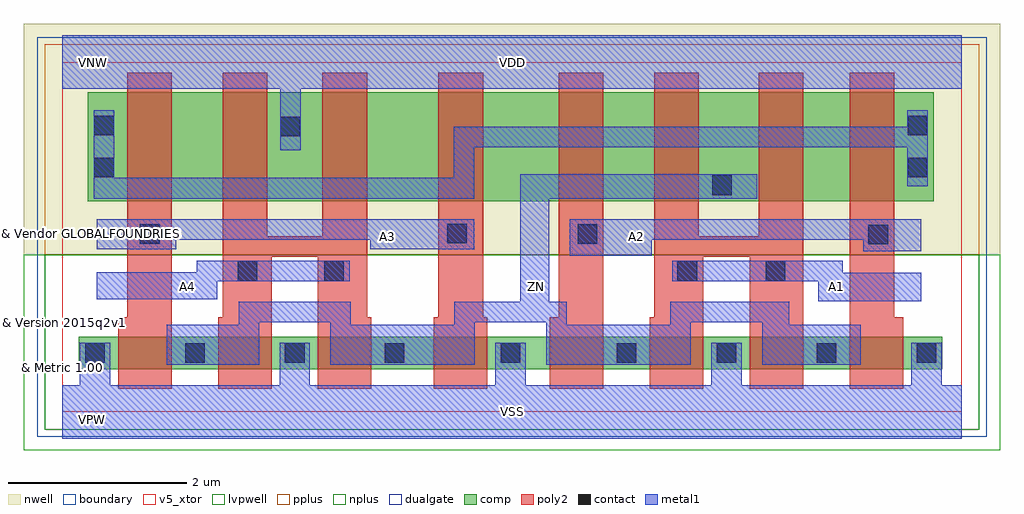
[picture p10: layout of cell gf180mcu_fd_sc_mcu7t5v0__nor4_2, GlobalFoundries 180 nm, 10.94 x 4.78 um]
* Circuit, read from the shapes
.subckt gf180mcu_fd_sc_mcu7t5v0__nor4_2 A1 A2 A3 A4 VDD VNW VSS ZN
XM1 ZN A3 VSS VSUBS nfet_05v0 w=0.36u l=0.6u m=2
XM2 VSS A4 ZN VSUBS nfet_05v0 w=0.36u l=0.6u m=2
XM3 ZN A2 VSS VSUBS nfet_05v0 w=0.36u l=0.6u m=2
XM4 VSS A1 ZN VSUBS nfet_05v0 w=0.36u l=0.6u m=2
XM5 n1 A3 n2 VNW pfet_05v0 w=1.22u l=0.5u
XM6 VDD A4 n1 VNW pfet_05v0 w=1.22u l=0.5u
XM7 n3 A4 VDD VNW pfet_05v0 w=1.22u l=0.5u
XM8 n4 A3 n3 VNW pfet_05v0 w=1.22u l=0.5u
XM9 n5 A2 n4 VNW pfet_05v0 w=1.22u l=0.5u
XM10 ZN A1 n5 VNW pfet_05v0 w=1.22u l=0.5u
XM11 n6 A1 ZN VNW pfet_05v0 w=1.22u l=0.5u
XM12 n2 A2 n6 VNW pfet_05v0 w=1.22u l=0.5u
.ends

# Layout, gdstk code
import gdstk
lib = gdstk.Library(unit=1e-6, precision=1e-09)
def R(c, l, rs):  # rectangles x0, y0, x1, y1
    for r in rs: c.add(gdstk.rectangle(r[:2], r[2:], *l))
def A(c, l, x, y, w, h, nx, ny, dx, dy):  # array of equal rectangles
    R(c, l, [(x+i*dx, y+j*dy, x+i*dx+w, y+j*dy+h) for i in range(nx) for j in range(ny)])
def P(c, l, *ps):  # polygons
    for p in ps: c.add(gdstk.Polygon(p, *l))
boundary = (0, 0)
nwell = (21, 0)
comp = (22, 0)
poly2 = (30, 0)
pplus = (31, 0)
nplus = (32, 0)
contact = (33, 0)
metal1 = (34, 0)
dualgate = (55, 0)
v5_xtor = (112, 1)
lvpwell = (204, 0)

gf180mcu_fd_sc_mcu7t5v0_ = lib.new_cell('gf180mcu_fd_sc_mcu7t5v0__nor4_2')
R(gf180mcu_fd_sc_mcu7t5v0_, boundary, [(0,0,10.08,3.92)])
R(gf180mcu_fd_sc_mcu7t5v0_, nwell, [(-0.43,1.76,10.51,4.35)])
R(gf180mcu_fd_sc_mcu7t5v0_, comp, [(0.185,0.48,9.865,0.84), (0.285,2.36,9.765,3.58)])
P(gf180mcu_fd_sc_mcu7t5v0_, poly2, [(0.625,0.26),(0.625,1.06),(0.725,1.06),(0.725,3.8),(1.225,3.8),(1.225,0.26)],
  [(1.745,0.26),(1.745,1.06),(1.795,1.06),(1.795,3.8),(2.295,3.8),(2.295,1.97),(2.915,1.97),(2.915,3.8),(3.415,3.8),(3.415,1.06),(3.465,1.06),(3.465,0.26),(2.865,0.26),(2.865,1.74),(2.345,1.74),(2.345,0.26)],
  [(4.165,0.26),(4.165,1.06),(4.215,1.06),(4.215,3.8),(4.715,3.8),(4.715,1.06),(4.765,1.06),(4.765,0.26)],
  [(5.465,0.26),(5.465,1.06),(5.565,1.06),(5.565,3.8),(6.065,3.8),(6.065,0.26)],
  [(6.585,0.26),(6.585,1.06),(6.635,1.06),(6.635,3.8),(7.135,3.8),(7.135,1.97),(7.805,1.97),(7.805,3.8),(8.305,3.8),(8.305,0.26),(7.705,0.26),(7.705,1.74),(7.185,1.74),(7.185,0.26)],
  [(8.825,0.26),(8.825,3.8),(9.325,3.8),(9.325,1.06),(9.425,1.06),(9.425,0.26)])
R(gf180mcu_fd_sc_mcu7t5v0_, pplus, [(-0.2,1.76,10.28,4.12)])
R(gf180mcu_fd_sc_mcu7t5v0_, nplus, [(-0.2,-0.2,10.28,1.76)])
A(gf180mcu_fd_sc_mcu7t5v0_, contact, 0.255, 0.55, 0.22, 0.22, 4, 1, 1.12, 0)
A(gf180mcu_fd_sc_mcu7t5v0_, contact, 6.215, 0.55, 0.22, 0.22, 4, 1, 1.12, 0)
R(gf180mcu_fd_sc_mcu7t5v0_, contact, [(4.915,0.55,5.135,0.77), (1.965,1.47,2.185,1.69), (2.935,1.47,3.155,1.69), (6.895,1.47,7.115,1.69), (7.885,1.47,8.105,1.69), (9.035,1.88,9.255,2.1), (0.87,1.885,1.09,2.105), (5.775,1.885,5.995,2.105), (4.315,1.89,4.535,2.11), (7.285,2.43,7.505,2.65), (0.355,2.63,0.575,2.85), (9.475,2.63,9.695,2.85), (2.445,3.09,2.665,3.31), (0.355,3.1,0.575,3.32), (9.475,3.1,9.695,3.32)])
P(gf180mcu_fd_sc_mcu7t5v0_, metal1, [(0.385,1.265),(0.385,1.565),(1.505,1.565),(1.505,1.695),(3.22,1.695),(3.22,1.465),(1.735,1.465),(1.735,1.265)],
  [(0.385,1.825),(0.385,2.16),(4.615,2.16),(4.615,1.825),(3.45,1.825),(3.45,1.93),(1.275,1.93),(1.275,1.825)],
  [(1.17,0.53),(1.17,0.975),(1.975,0.975),(1.975,1.235),(3.235,1.235),(3.235,0.975),(4.395,0.975),(4.395,1.235),(5.13,1.235),(5.13,2.665),(7.79,2.665),(7.79,2.39),(5.46,2.39),(5.46,1.235),(5.655,1.235),(5.655,0.975),(6.815,0.975),(6.815,1.235),(8.145,1.235),(8.145,0.975),(8.95,0.975),(8.95,0.53),(7.845,0.53),(7.845,1.005),(7.045,1.005),(7.045,0.53),(5.425,0.53),(5.425,1.005),(4.625,1.005),(4.625,0.53),(3.005,0.53),(3.005,1.005),(2.205,1.005),(2.205,0.53)],
  [(8.47,1.24),(8.47,1.465),(6.835,1.465),(6.835,1.695),(8.745,1.695),(8.745,1.56),(9.63,1.56),(9.63,1.24)],
  [(5.69,1.75),(5.69,2.16),(9.63,2.16),(9.63,1.8),(8.975,1.8),(8.975,1.93),(6.605,1.93),(6.605,1.75)],
  [(0.35,2.39),(0.35,3.38),(0.58,3.38),(0.58,2.625),(4.385,2.625),(4.385,3.195),(9.47,3.195),(9.47,3.38),(9.7,3.38),(9.7,2.53),(9.47,2.53),(9.47,2.965),(4.615,2.965),(4.615,2.39)],
  [(0,-0.3),(0,0.3),(0.195,0.3),(0.195,0.775),(0.535,0.775),(0.535,0.3),(2.435,0.3),(2.435,0.775),(2.775,0.775),(2.775,0.3),(4.855,0.3),(4.855,0.775),(5.195,0.775),(5.195,0.3),(7.275,0.3),(7.275,0.775),(7.615,0.775),(7.615,0.3),(9.515,0.3),(9.515,0.775),(9.855,0.775),(9.855,0.3),(10.08,0.3),(10.08,-0.3)],
  [(2.44,2.935),(2.44,3.62),(0,3.62),(0,4.22),(10.08,4.22),(10.08,3.62),(2.67,3.62),(2.67,2.935)])
R(gf180mcu_fd_sc_mcu7t5v0_, dualgate, [(-0.28,-0.28,10.36,4.2)])
R(gf180mcu_fd_sc_mcu7t5v0_, v5_xtor, [(0,0,10.08,3.92)])
R(gf180mcu_fd_sc_mcu7t5v0_, lvpwell, [(-0.43,-0.43,10.51,1.76)])
gf180mcu_fd_sc_mcu7t5v0_.add(gdstk.Label('A3', (3.64,1.96), layer=34, texttype=10))
gf180mcu_fd_sc_mcu7t5v0_.add(gdstk.Label('A4', (1.4,1.4), layer=34, texttype=10))
gf180mcu_fd_sc_mcu7t5v0_.add(gdstk.Label('VDD', (5.04,3.92), layer=34, texttype=10))
gf180mcu_fd_sc_mcu7t5v0_.add(gdstk.Label('VSS', (5.04,0), layer=34, texttype=10))
gf180mcu_fd_sc_mcu7t5v0_.add(gdstk.Label('ZN', (5.32,1.4), layer=34, texttype=10))
gf180mcu_fd_sc_mcu7t5v0_.add(gdstk.Label('A1', (8.68,1.4), layer=34, texttype=10))
gf180mcu_fd_sc_mcu7t5v0_.add(gdstk.Label('A2', (6.44,1.96), layer=34, texttype=10))
gf180mcu_fd_sc_mcu7t5v0_.add(gdstk.Label('& Vendor GLOBALFOUNDRIES', (0,2), layer=63, texttype=63))
gf180mcu_fd_sc_mcu7t5v0_.add(gdstk.Label('& Product GF018hv5v_mcu_sc7', (0,1.5), layer=63, texttype=63))
gf180mcu_fd_sc_mcu7t5v0_.add(gdstk.Label('& Version 2015q2v1', (0,1), layer=63, texttype=63))
gf180mcu_fd_sc_mcu7t5v0_.add(gdstk.Label('& Metric 1.00', (0,0.5), layer=63, texttype=63))
gf180mcu_fd_sc_mcu7t5v0_.add(gdstk.Label('VNW', (0.345,3.92), layer=21, texttype=10))
gf180mcu_fd_sc_mcu7t5v0_.add(gdstk.Label('VPW', (0.34,-0.085), layer=204, texttype=10))

lib.write_gds('gf180mcu_fd_sc_mcu7t5v0__nor4_2.gds')
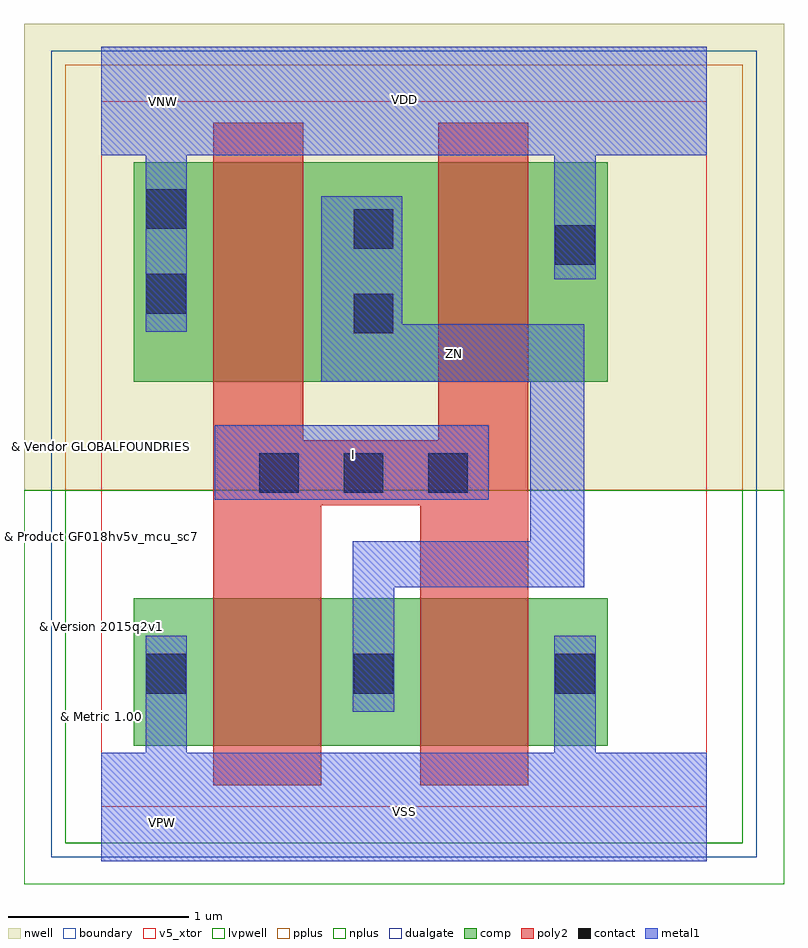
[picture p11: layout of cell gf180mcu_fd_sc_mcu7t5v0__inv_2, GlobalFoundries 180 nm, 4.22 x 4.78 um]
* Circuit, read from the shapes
.subckt gf180mcu_fd_sc_mcu7t5v0__inv_2 I VDD VNW VSS ZN
XM1 ZN I VSS VSUBS nfet_05v0 w=0.82u l=0.6u m=2
XM2 ZN I VDD VNW pfet_05v0 w=1.22u l=0.5u m=2
.ends

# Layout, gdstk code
import gdstk
lib = gdstk.Library(unit=1e-6, precision=1e-09)
def R(c, l, rs):  # rectangles x0, y0, x1, y1
    for r in rs: c.add(gdstk.rectangle(r[:2], r[2:], *l))
def A(c, l, x, y, w, h, nx, ny, dx, dy):  # array of equal rectangles
    R(c, l, [(x+i*dx, y+j*dy, x+i*dx+w, y+j*dy+h) for i in range(nx) for j in range(ny)])
def P(c, l, *ps):  # polygons
    for p in ps: c.add(gdstk.Polygon(p, *l))
boundary = (0, 0)
nwell = (21, 0)
comp = (22, 0)
poly2 = (30, 0)
pplus = (31, 0)
nplus = (32, 0)
contact = (33, 0)
metal1 = (34, 0)
dualgate = (55, 0)
v5_xtor = (112, 1)
lvpwell = (204, 0)

gf180mcu_fd_sc_mcu7t5v0_ = lib.new_cell('gf180mcu_fd_sc_mcu7t5v0__inv_2')
R(gf180mcu_fd_sc_mcu7t5v0_, boundary, [(0,0,3.36,3.92)])
R(gf180mcu_fd_sc_mcu7t5v0_, nwell, [(-0.43,1.76,3.79,4.35)])
R(gf180mcu_fd_sc_mcu7t5v0_, comp, [(0.18,0.34,2.81,1.16), (0.18,2.36,2.81,3.58)])
P(gf180mcu_fd_sc_mcu7t5v0_, poly2, [(0.62,0.12),(0.62,3.8),(1.12,3.8),(1.12,2.035),(1.87,2.035),(1.87,3.8),(2.37,3.8),(2.37,0.12),(1.77,0.12),(1.77,1.675),(1.22,1.675),(1.22,0.12)])
R(gf180mcu_fd_sc_mcu7t5v0_, pplus, [(-0.2,1.76,3.56,4.12)])
R(gf180mcu_fd_sc_mcu7t5v0_, nplus, [(-0.2,-0.2,3.56,1.76)])
A(gf180mcu_fd_sc_mcu7t5v0_, contact, 0.875, 1.745, 0.22, 0.22, 3, 1, 0.47, 0)
R(gf180mcu_fd_sc_mcu7t5v0_, contact, [(0.25,0.63,0.47,0.85), (1.4,0.63,1.62,0.85), (2.52,0.63,2.74,0.85), (1.4,2.63,1.62,2.85), (0.25,2.74,0.47,2.96), (2.52,3.01,2.74,3.23), (1.4,3.1,1.62,3.32), (0.25,3.21,0.47,3.43)])
R(gf180mcu_fd_sc_mcu7t5v0_, metal1, [(0.63,1.705,2.15,2.12)])
P(gf180mcu_fd_sc_mcu7t5v0_, metal1, [(1.395,0.53),(1.395,1.475),(2.38,1.475),(2.38,2.36),(1.22,2.36),(1.22,3.39),(1.67,3.39),(1.67,2.68),(2.68,2.68),(2.68,1.22),(1.625,1.22),(1.625,0.53)],
  [(0,-0.3),(0,0.3),(0.245,0.3),(0.245,0.95),(0.475,0.95),(0.475,0.3),(2.515,0.3),(2.515,0.95),(2.745,0.95),(2.745,0.3),(3.36,0.3),(3.36,-0.3)],
  [(0.245,2.64),(0.245,3.62),(0,3.62),(0,4.22),(3.36,4.22),(3.36,3.62),(2.745,3.62),(2.745,2.93),(2.515,2.93),(2.515,3.62),(0.475,3.62),(0.475,2.64)])
R(gf180mcu_fd_sc_mcu7t5v0_, dualgate, [(-0.28,-0.28,3.64,4.2)])
R(gf180mcu_fd_sc_mcu7t5v0_, v5_xtor, [(0,0,3.36,3.92)])
R(gf180mcu_fd_sc_mcu7t5v0_, lvpwell, [(-0.43,-0.43,3.79,1.76)])
gf180mcu_fd_sc_mcu7t5v0_.add(gdstk.Label('VSS', (1.68,-0.025), layer=34, texttype=10))
gf180mcu_fd_sc_mcu7t5v0_.add(gdstk.Label('ZN', (1.96,2.52), layer=34, texttype=10))
gf180mcu_fd_sc_mcu7t5v0_.add(gdstk.Label('I', (1.4,1.96), layer=34, texttype=10))
gf180mcu_fd_sc_mcu7t5v0_.add(gdstk.Label('VDD', (1.68,3.93), layer=34, texttype=10))
gf180mcu_fd_sc_mcu7t5v0_.add(gdstk.Label('& Vendor GLOBALFOUNDRIES', (0,2), layer=63, texttype=63))
gf180mcu_fd_sc_mcu7t5v0_.add(gdstk.Label('& Product GF018hv5v_mcu_sc7', (0,1.5), layer=63, texttype=63))
gf180mcu_fd_sc_mcu7t5v0_.add(gdstk.Label('& Version 2015q2v1', (0,1), layer=63, texttype=63))
gf180mcu_fd_sc_mcu7t5v0_.add(gdstk.Label('& Metric 1.00', (0,0.5), layer=63, texttype=63))
gf180mcu_fd_sc_mcu7t5v0_.add(gdstk.Label('VNW', (0.345,3.92), layer=21, texttype=10))
gf180mcu_fd_sc_mcu7t5v0_.add(gdstk.Label('VPW', (0.34,-0.085), layer=204, texttype=10))

lib.write_gds('gf180mcu_fd_sc_mcu7t5v0__inv_2.gds')
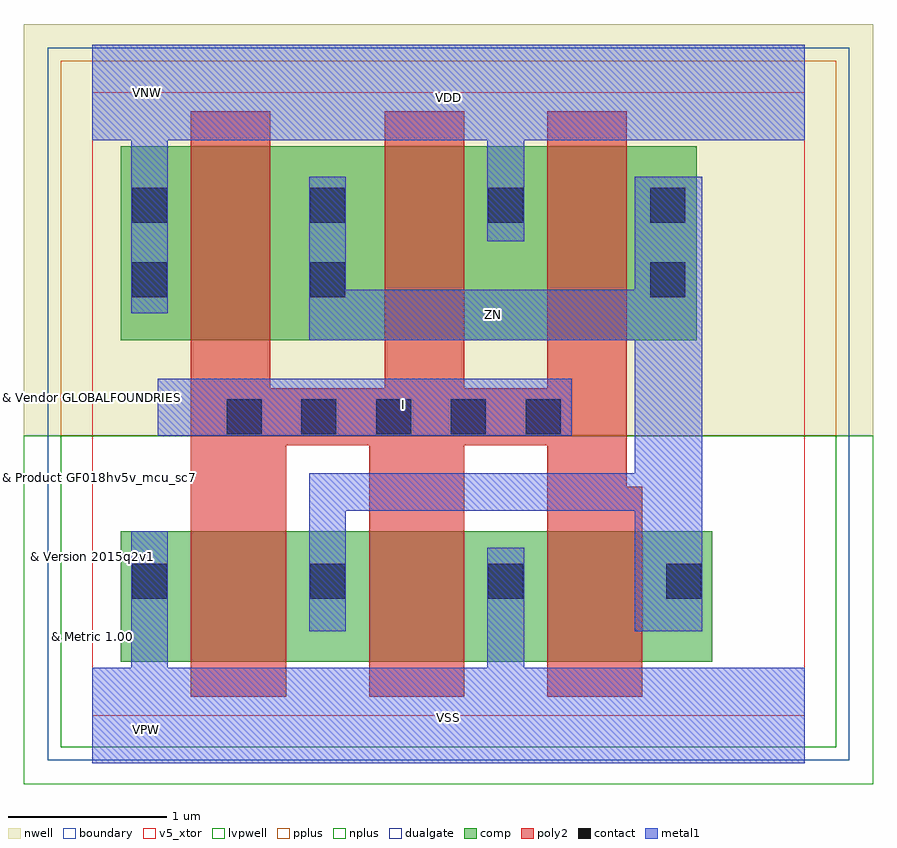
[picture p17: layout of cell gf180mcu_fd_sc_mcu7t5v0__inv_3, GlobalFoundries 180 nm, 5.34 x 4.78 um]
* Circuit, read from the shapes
.subckt gf180mcu_fd_sc_mcu7t5v0__inv_3 I VDD VNW VSS ZN
XM1 ZN I VSS VSUBS nfet_05v0 w=0.82u l=0.6u m=3
XM2 ZN I VDD VNW pfet_05v0 w=1.22u l=0.5u m=3
.ends

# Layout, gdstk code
import gdstk
lib = gdstk.Library(unit=1e-6, precision=1e-09)
def R(c, l, rs):  # rectangles x0, y0, x1, y1
    for r in rs: c.add(gdstk.rectangle(r[:2], r[2:], *l))
def A(c, l, x, y, w, h, nx, ny, dx, dy):  # array of equal rectangles
    R(c, l, [(x+i*dx, y+j*dy, x+i*dx+w, y+j*dy+h) for i in range(nx) for j in range(ny)])
def P(c, l, *ps):  # polygons
    for p in ps: c.add(gdstk.Polygon(p, *l))
boundary = (0, 0)
nwell = (21, 0)
comp = (22, 0)
poly2 = (30, 0)
pplus = (31, 0)
nplus = (32, 0)
contact = (33, 0)
metal1 = (34, 0)
dualgate = (55, 0)
v5_xtor = (112, 1)
lvpwell = (204, 0)

gf180mcu_fd_sc_mcu7t5v0_ = lib.new_cell('gf180mcu_fd_sc_mcu7t5v0__inv_3')
R(gf180mcu_fd_sc_mcu7t5v0_, boundary, [(0,0,4.48,3.92)])
R(gf180mcu_fd_sc_mcu7t5v0_, nwell, [(-0.43,1.76,4.91,4.35)])
R(gf180mcu_fd_sc_mcu7t5v0_, comp, [(0.18,0.34,3.9,1.16), (0.18,2.36,3.8,3.58)])
P(gf180mcu_fd_sc_mcu7t5v0_, poly2, [(0.62,0.12),(0.62,3.8),(1.12,3.8),(1.12,2.06),(1.84,2.06),(1.84,3.8),(2.34,3.8),(2.34,2.06),(2.86,2.06),(2.86,3.8),(3.36,3.8),(3.36,1.44),(3.46,1.44),(3.46,0.12),(2.86,0.12),(2.86,1.7),(2.34,1.7),(2.34,0.12),(1.74,0.12),(1.74,1.7),(1.22,1.7),(1.22,0.12)])
R(gf180mcu_fd_sc_mcu7t5v0_, pplus, [(-0.2,1.76,4.68,4.12)])
R(gf180mcu_fd_sc_mcu7t5v0_, nplus, [(-0.2,-0.2,4.68,1.76)])
A(gf180mcu_fd_sc_mcu7t5v0_, contact, 0.25, 0.735, 0.22, 0.22, 4, 1, 1.12, 0)
A(gf180mcu_fd_sc_mcu7t5v0_, contact, 0.845, 1.77, 0.22, 0.22, 5, 1, 0.47, 0)
A(gf180mcu_fd_sc_mcu7t5v0_, contact, 0.25, 3.1, 0.22, 0.22, 3, 1, 1.12, 0)
R(gf180mcu_fd_sc_mcu7t5v0_, contact, [(0.25,2.63,0.47,2.85), (1.37,2.63,1.59,2.85), (3.51,2.63,3.73,2.85), (3.51,3.1,3.73,3.32)])
R(gf180mcu_fd_sc_mcu7t5v0_, metal1, [(0.41,1.76,3.015,2.12)])
P(gf180mcu_fd_sc_mcu7t5v0_, metal1, [(1.365,0.53),(1.365,1.525),(3.41,1.525),(3.41,2.36),(1.365,2.36),(1.365,3.39),(1.595,3.39),(1.595,2.68),(3.41,2.68),(3.41,3.39),(3.835,3.39),(3.835,0.53),(3.41,0.53),(3.41,1.29),(1.595,1.29),(1.595,0.53)],
  [(0,-0.3),(0,0.3),(0.245,0.3),(0.245,1.16),(0.475,1.16),(0.475,0.3),(2.485,0.3),(2.485,1.055),(2.715,1.055),(2.715,0.3),(4.48,0.3),(4.48,-0.3)],
  [(0.245,2.53),(0.245,3.62),(0,3.62),(0,4.22),(4.48,4.22),(4.48,3.62),(2.715,3.62),(2.715,2.985),(2.485,2.985),(2.485,3.62),(0.475,3.62),(0.475,2.53)])
R(gf180mcu_fd_sc_mcu7t5v0_, dualgate, [(-0.28,-0.28,4.76,4.2)])
R(gf180mcu_fd_sc_mcu7t5v0_, v5_xtor, [(0,0,4.48,3.92)])
R(gf180mcu_fd_sc_mcu7t5v0_, lvpwell, [(-0.43,-0.43,4.91,1.76)])
gf180mcu_fd_sc_mcu7t5v0_.add(gdstk.Label('VSS', (2.24,-0.01), layer=34, texttype=10))
gf180mcu_fd_sc_mcu7t5v0_.add(gdstk.Label('ZN', (2.52,2.52), layer=34, texttype=10))
gf180mcu_fd_sc_mcu7t5v0_.add(gdstk.Label('I', (1.96,1.96), layer=34, texttype=10))
gf180mcu_fd_sc_mcu7t5v0_.add(gdstk.Label('VDD', (2.24,3.885), layer=34, texttype=10))
gf180mcu_fd_sc_mcu7t5v0_.add(gdstk.Label('& Vendor GLOBALFOUNDRIES', (0,2), layer=63, texttype=63))
gf180mcu_fd_sc_mcu7t5v0_.add(gdstk.Label('& Product GF018hv5v_mcu_sc7', (0,1.5), layer=63, texttype=63))
gf180mcu_fd_sc_mcu7t5v0_.add(gdstk.Label('& Version 2015q2v1', (0,1), layer=63, texttype=63))
gf180mcu_fd_sc_mcu7t5v0_.add(gdstk.Label('& Metric 1.00', (0,0.5), layer=63, texttype=63))
gf180mcu_fd_sc_mcu7t5v0_.add(gdstk.Label('VNW', (0.345,3.92), layer=21, texttype=10))
gf180mcu_fd_sc_mcu7t5v0_.add(gdstk.Label('VPW', (0.34,-0.085), layer=204, texttype=10))

lib.write_gds('gf180mcu_fd_sc_mcu7t5v0__inv_3.gds')
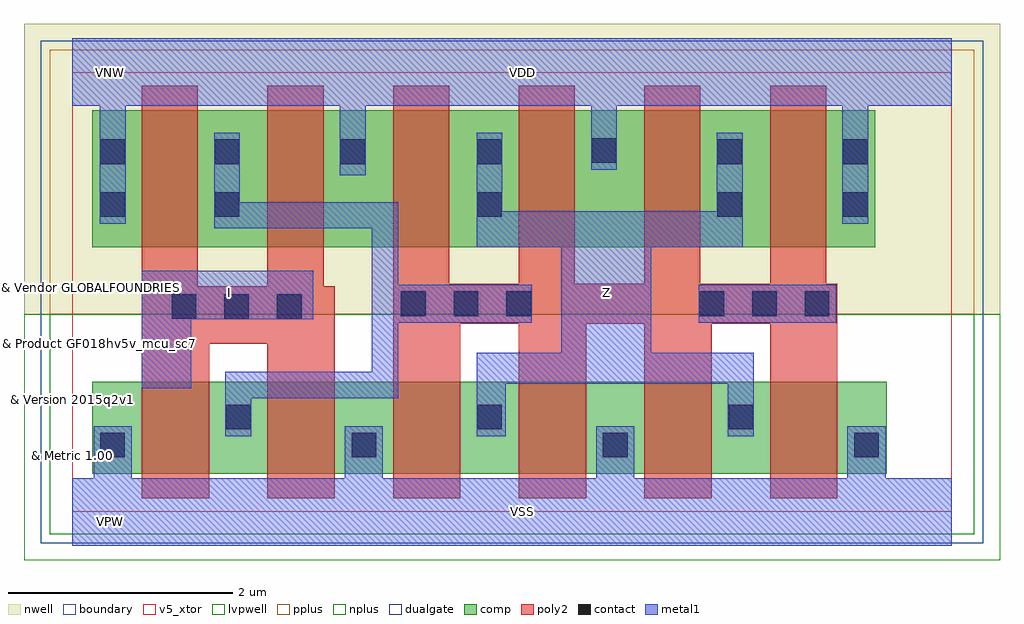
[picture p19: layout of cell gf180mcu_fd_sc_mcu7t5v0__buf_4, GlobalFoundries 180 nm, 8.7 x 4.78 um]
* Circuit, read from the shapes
.subckt gf180mcu_fd_sc_mcu7t5v0__buf_4 I VDD VNW VSS Z
XM1 n1 I VSS VSUBS nfet_05v0 w=0.82u l=0.6u m=2
XM2 Z n1 VSS VSUBS nfet_05v0 w=0.82u l=0.6u m=4
XM3 n1 I VDD VNW pfet_05v0 w=1.22u l=0.5u m=2
XM4 Z n1 VDD VNW pfet_05v0 w=1.22u l=0.5u m=4
.ends

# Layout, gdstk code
import gdstk
lib = gdstk.Library(unit=1e-6, precision=1e-09)
def R(c, l, rs):  # rectangles x0, y0, x1, y1
    for r in rs: c.add(gdstk.rectangle(r[:2], r[2:], *l))
def A(c, l, x, y, w, h, nx, ny, dx, dy):  # array of equal rectangles
    R(c, l, [(x+i*dx, y+j*dy, x+i*dx+w, y+j*dy+h) for i in range(nx) for j in range(ny)])
def P(c, l, *ps):  # polygons
    for p in ps: c.add(gdstk.Polygon(p, *l))
boundary = (0, 0)
nwell = (21, 0)
comp = (22, 0)
poly2 = (30, 0)
pplus = (31, 0)
nplus = (32, 0)
contact = (33, 0)
metal1 = (34, 0)
dualgate = (55, 0)
v5_xtor = (112, 1)
lvpwell = (204, 0)

gf180mcu_fd_sc_mcu7t5v0_ = lib.new_cell('gf180mcu_fd_sc_mcu7t5v0__buf_4')
R(gf180mcu_fd_sc_mcu7t5v0_, boundary, [(0,0,7.84,3.92)])
R(gf180mcu_fd_sc_mcu7t5v0_, nwell, [(-0.43,1.76,8.27,4.35)])
R(gf180mcu_fd_sc_mcu7t5v0_, comp, [(0.18,0.34,7.26,1.16), (0.18,2.36,7.16,3.58)])
P(gf180mcu_fd_sc_mcu7t5v0_, poly2, [(0.62,0.12),(0.62,3.8),(1.12,3.8),(1.12,2.01),(1.74,2.01),(1.74,3.8),(2.24,3.8),(2.24,2.01),(2.34,2.01),(2.34,0.12),(1.74,0.12),(1.74,1.5),(1.22,1.5),(1.22,0.12)],
  [(2.86,0.12),(2.86,3.8),(3.36,3.8),(3.36,2.035),(3.98,2.035),(3.98,3.8),(4.48,3.8),(4.48,2.035),(5.1,2.035),(5.1,3.8),(5.6,3.8),(5.6,2.035),(6.22,2.035),(6.22,3.8),(6.72,3.8),(6.72,2.035),(6.82,2.035),(6.82,0.12),(6.22,0.12),(6.22,1.675),(5.7,1.675),(5.7,0.12),(5.1,0.12),(5.1,1.675),(4.58,1.675),(4.58,0.12),(3.98,0.12),(3.98,1.675),(3.46,1.675),(3.46,0.12)])
R(gf180mcu_fd_sc_mcu7t5v0_, pplus, [(-0.2,1.76,8.04,4.12)])
R(gf180mcu_fd_sc_mcu7t5v0_, nplus, [(-0.2,-0.2,8.04,1.76)])
A(gf180mcu_fd_sc_mcu7t5v0_, contact, 0.25, 0.485, 0.22, 0.22, 4, 1, 2.24, 0)
A(gf180mcu_fd_sc_mcu7t5v0_, contact, 1.37, 0.735, 0.22, 0.22, 3, 1, 2.24, 0)
A(gf180mcu_fd_sc_mcu7t5v0_, contact, 0.885, 1.72, 0.22, 0.22, 3, 1, 0.47, 0)
A(gf180mcu_fd_sc_mcu7t5v0_, contact, 2.93, 1.745, 0.22, 0.22, 3, 1, 0.47, 0)
A(gf180mcu_fd_sc_mcu7t5v0_, contact, 5.59, 1.745, 0.22, 0.22, 3, 1, 0.47, 0)
R(gf180mcu_fd_sc_mcu7t5v0_, contact, [(0.25,2.63,0.47,2.85), (1.27,2.63,1.49,2.85), (3.61,2.63,3.83,2.85), (5.75,2.63,5.97,2.85), (6.87,2.63,7.09,2.85), (0.25,3.1,0.47,3.32), (1.27,3.1,1.49,3.32), (2.39,3.1,2.61,3.32), (3.61,3.1,3.83,3.32), (5.75,3.1,5.97,3.32), (6.87,3.1,7.09,3.32), (4.63,3.11,4.85,3.33)])
R(gf180mcu_fd_sc_mcu7t5v0_, metal1, [(5.585,1.685,6.81,2.025)])
P(gf180mcu_fd_sc_mcu7t5v0_, metal1, [(0.62,1.1),(0.62,2.15),(2.15,2.15),(2.15,1.715),(1.06,1.715),(1.06,1.1)],
  [(1.365,0.675),(1.365,1.25),(2.67,1.25),(2.67,2.53),(1.265,2.53),(1.265,3.38),(1.495,3.38),(1.495,2.76),(2.905,2.76),(2.905,2.025),(4.095,2.025),(4.095,1.685),(2.905,1.685),(2.905,1.015),(1.595,1.015),(1.595,0.675)],
  [(3.605,0.675),(3.605,1.42),(4.36,1.42),(4.36,2.36),(3.605,2.36),(3.605,3.38),(3.835,3.38),(3.835,2.68),(5.745,2.68),(5.745,3.38),(5.975,3.38),(5.975,2.36),(5.16,2.36),(5.16,1.42),(6.075,1.42),(6.075,0.675),(5.845,0.675),(5.845,1.14),(3.865,1.14),(3.865,0.675)],
  [(0,-0.3),(0,0.3),(0.19,0.3),(0.19,0.765),(0.53,0.765),(0.53,0.3),(2.43,0.3),(2.43,0.765),(2.77,0.765),(2.77,0.3),(4.67,0.3),(4.67,0.765),(5.01,0.765),(5.01,0.3),(6.91,0.3),(6.91,0.765),(7.25,0.765),(7.25,0.3),(7.84,0.3),(7.84,-0.3)],
  [(0.245,2.57),(0.245,3.62),(0,3.62),(0,4.22),(7.84,4.22),(7.84,3.62),(7.095,3.62),(7.095,2.57),(6.865,2.57),(6.865,3.62),(4.855,3.62),(4.855,3.05),(4.625,3.05),(4.625,3.62),(2.615,3.62),(2.615,3),(2.385,3),(2.385,3.62),(0.475,3.62),(0.475,2.57)])
R(gf180mcu_fd_sc_mcu7t5v0_, dualgate, [(-0.28,-0.28,8.12,4.2)])
R(gf180mcu_fd_sc_mcu7t5v0_, v5_xtor, [(0,0,7.84,3.92)])
R(gf180mcu_fd_sc_mcu7t5v0_, lvpwell, [(-0.43,-0.43,8.27,1.76)])
gf180mcu_fd_sc_mcu7t5v0_.add(gdstk.Label('Z', (4.76,1.96), layer=34, texttype=10))
gf180mcu_fd_sc_mcu7t5v0_.add(gdstk.Label('I', (1.4,1.96), layer=34, texttype=10))
gf180mcu_fd_sc_mcu7t5v0_.add(gdstk.Label('VDD', (4.01,3.92), layer=34, texttype=10))
gf180mcu_fd_sc_mcu7t5v0_.add(gdstk.Label('VSS', (4.01,0), layer=34, texttype=10))
gf180mcu_fd_sc_mcu7t5v0_.add(gdstk.Label('& Vendor GLOBALFOUNDRIES', (0,2), layer=63, texttype=63))
gf180mcu_fd_sc_mcu7t5v0_.add(gdstk.Label('& Product GF018hv5v_mcu_sc7', (0,1.5), layer=63, texttype=63))
gf180mcu_fd_sc_mcu7t5v0_.add(gdstk.Label('& Version 2015q2v1', (0,1), layer=63, texttype=63))
gf180mcu_fd_sc_mcu7t5v0_.add(gdstk.Label('& Metric 1.00', (0,0.5), layer=63, texttype=63))
gf180mcu_fd_sc_mcu7t5v0_.add(gdstk.Label('VNW', (0.345,3.92), layer=21, texttype=10))
gf180mcu_fd_sc_mcu7t5v0_.add(gdstk.Label('VPW', (0.34,-0.085), layer=204, texttype=10))

lib.write_gds('gf180mcu_fd_sc_mcu7t5v0__buf_4.gds')
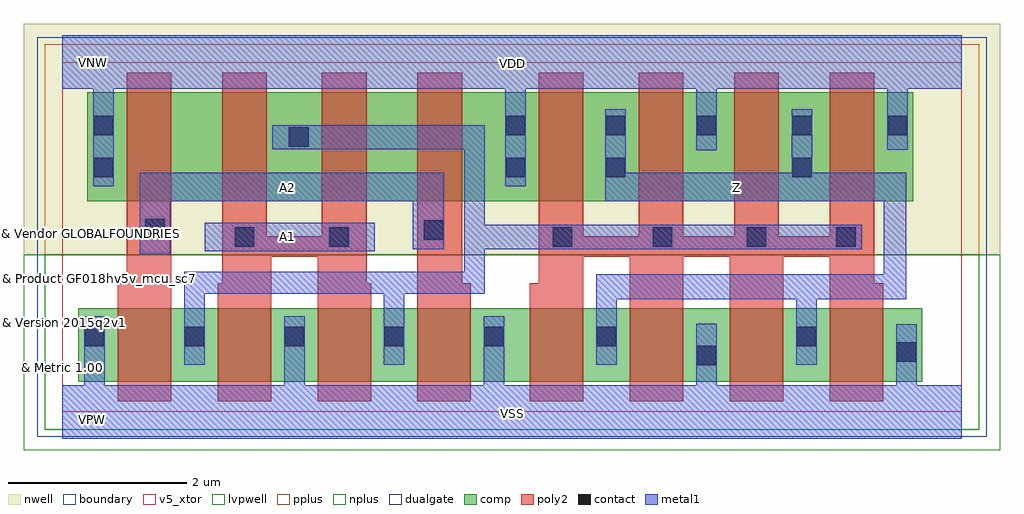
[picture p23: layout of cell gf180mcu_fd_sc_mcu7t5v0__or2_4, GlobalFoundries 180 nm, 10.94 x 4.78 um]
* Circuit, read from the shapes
.subckt gf180mcu_fd_sc_mcu7t5v0__or2_4 A1 A2 VDD VNW VSS Z
XM1 n1 A2 VSS VSUBS nfet_05v0 w=0.82u l=0.6u m=2
XM2 VSS A1 n1 VSUBS nfet_05v0 w=0.82u l=0.6u m=2
XM3 Z n1 VSS VSUBS nfet_05v0 w=0.82u l=0.6u m=4
XM4 n2 A2 VDD VNW pfet_05v0 w=1.22u l=0.5u
XM5 n1 A1 n2 VNW pfet_05v0 w=1.22u l=0.5u
XM6 n3 A1 n1 VNW pfet_05v0 w=1.22u l=0.5u
XM7 VDD A2 n3 VNW pfet_05v0 w=1.22u l=0.5u
XM8 Z n1 VDD VNW pfet_05v0 w=1.22u l=0.5u m=4
.ends

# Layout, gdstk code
import gdstk
lib = gdstk.Library(unit=1e-6, precision=1e-09)
def R(c, l, rs):  # rectangles x0, y0, x1, y1
    for r in rs: c.add(gdstk.rectangle(r[:2], r[2:], *l))
def A(c, l, x, y, w, h, nx, ny, dx, dy):  # array of equal rectangles
    R(c, l, [(x+i*dx, y+j*dy, x+i*dx+w, y+j*dy+h) for i in range(nx) for j in range(ny)])
def P(c, l, *ps):  # polygons
    for p in ps: c.add(gdstk.Polygon(p, *l))
boundary = (0, 0)
nwell = (21, 0)
comp = (22, 0)
poly2 = (30, 0)
pplus = (31, 0)
nplus = (32, 0)
contact = (33, 0)
metal1 = (34, 0)
dualgate = (55, 0)
v5_xtor = (112, 1)
lvpwell = (204, 0)

gf180mcu_fd_sc_mcu7t5v0_ = lib.new_cell('gf180mcu_fd_sc_mcu7t5v0__or2_4')
R(gf180mcu_fd_sc_mcu7t5v0_, boundary, [(0,0,10.08,3.92)])
R(gf180mcu_fd_sc_mcu7t5v0_, nwell, [(-0.43,1.76,10.51,4.35)])
R(gf180mcu_fd_sc_mcu7t5v0_, comp, [(0.18,0.34,9.64,1.16), (0.28,2.36,9.54,3.58)])
P(gf180mcu_fd_sc_mcu7t5v0_, poly2, [(0.62,0.12),(0.62,1.44),(0.72,1.44),(0.72,3.8),(1.22,3.8),(1.22,0.12)],
  [(1.74,0.12),(1.74,1.44),(1.79,1.44),(1.79,3.8),(2.29,3.8),(2.29,1.97),(2.91,1.97),(2.91,3.8),(3.41,3.8),(3.41,1.44),(3.46,1.44),(3.46,0.12),(2.86,0.12),(2.86,1.74),(2.34,1.74),(2.34,0.12)],
  [(3.98,0.12),(3.98,3.8),(4.48,3.8),(4.48,1.44),(4.58,1.44),(4.58,0.12)],
  [(5.24,0.12),(5.24,1.44),(5.34,1.44),(5.34,3.8),(5.84,3.8),(5.84,1.97),(6.46,1.97),(6.46,3.8),(6.96,3.8),(6.96,1.97),(7.53,1.97),(7.53,3.8),(8.03,3.8),(8.03,1.97),(8.6,1.97),(8.6,3.8),(9.1,3.8),(9.1,1.44),(9.2,1.44),(9.2,0.12),(8.6,0.12),(8.6,1.74),(8.08,1.74),(8.08,0.12),(7.48,0.12),(7.48,1.74),(6.96,1.74),(6.96,0.12),(6.36,0.12),(6.36,1.74),(5.84,1.74),(5.84,0.12)])
R(gf180mcu_fd_sc_mcu7t5v0_, pplus, [(-0.2,1.76,10.28,4.12)])
R(gf180mcu_fd_sc_mcu7t5v0_, nplus, [(-0.2,-0.2,10.28,1.76)])
A(gf180mcu_fd_sc_mcu7t5v0_, contact, 0.25, 0.735, 0.22, 0.22, 5, 1, 1.12, 0)
A(gf180mcu_fd_sc_mcu7t5v0_, contact, 7.11, 3.1, 0.22, 0.22, 3, 1, 1.07, 0)
R(gf180mcu_fd_sc_mcu7t5v0_, contact, [(7.11,0.52,7.33,0.74), (9.35,0.56,9.57,0.78), (5.99,0.735,6.21,0.955), (8.23,0.735,8.45,0.955), (1.93,1.85,2.15,2.07), (2.99,1.85,3.21,2.07), (5.495,1.85,5.715,2.07), (6.615,1.85,6.835,2.07), (7.67,1.85,7.89,2.07), (8.675,1.85,8.895,2.07), (4.05,1.93,4.27,2.15), (0.93,1.945,1.15,2.165), (0.35,2.63,0.57,2.85), (4.97,2.63,5.19,2.85), (6.09,2.63,6.31,2.85), (8.18,2.63,8.4,2.85), (2.54,2.97,2.76,3.19), (0.35,3.1,0.57,3.32), (4.97,3.1,5.19,3.32), (6.09,3.1,6.31,3.32)])
R(gf180mcu_fd_sc_mcu7t5v0_, metal1, [(1.595,1.8,3.5,2.12)])
P(gf180mcu_fd_sc_mcu7t5v0_, metal1, [(0.87,1.765),(0.87,2.68),(4.275,2.68),(4.275,1.825),(3.93,1.825),(3.93,2.36),(1.21,2.36),(1.21,1.765)],
  [(1.365,0.53),(1.365,1.57),(4.505,1.57),(4.505,2.945),(2.35,2.945),(2.35,3.215),(4.735,3.215),(4.735,2.095),(8.96,2.095),(8.96,1.825),(4.735,1.825),(4.735,1.325),(3.835,1.325),(3.835,0.53),(3.605,0.53),(3.605,1.325),(1.595,1.325),(1.595,0.53)],
  [(5.985,0.53),(5.985,1.54),(9.205,1.54),(9.205,2.36),(6.085,2.36),(6.085,3.39),(6.315,3.39),(6.315,2.68),(8.175,2.68),(8.175,3.39),(8.405,3.39),(8.405,2.68),(9.46,2.68),(9.46,1.265),(8.455,1.265),(8.455,0.53),(8.225,0.53),(8.225,1.26),(6.215,1.26),(6.215,0.53)],
  [(0,-0.3),(0,0.3),(0.245,0.3),(0.245,1.07),(0.475,1.07),(0.475,0.3),(2.485,0.3),(2.485,1.07),(2.715,1.07),(2.715,0.3),(4.725,0.3),(4.725,1.07),(4.955,1.07),(4.955,0.3),(7.105,0.3),(7.105,0.985),(7.335,0.985),(7.335,0.3),(9.345,0.3),(9.345,0.98),(9.575,0.98),(9.575,0.3),(10.08,0.3),(10.08,-0.3)],
  [(0.345,2.53),(0.345,3.62),(0,3.62),(0,4.22),(10.08,4.22),(10.08,3.62),(9.475,3.62),(9.475,2.94),(9.245,2.94),(9.245,3.62),(7.335,3.62),(7.335,2.935),(7.105,2.935),(7.105,3.62),(5.195,3.62),(5.195,2.53),(4.965,2.53),(4.965,3.62),(0.575,3.62),(0.575,2.53)])
R(gf180mcu_fd_sc_mcu7t5v0_, dualgate, [(-0.28,-0.28,10.36,4.2)])
R(gf180mcu_fd_sc_mcu7t5v0_, v5_xtor, [(0,0,10.08,3.92)])
R(gf180mcu_fd_sc_mcu7t5v0_, lvpwell, [(-0.43,-0.43,10.51,1.76)])
gf180mcu_fd_sc_mcu7t5v0_.add(gdstk.Label('VDD', (5.04,3.905), layer=34, texttype=10))
gf180mcu_fd_sc_mcu7t5v0_.add(gdstk.Label('VSS', (5.04,-0.015), layer=34, texttype=10))
gf180mcu_fd_sc_mcu7t5v0_.add(gdstk.Label('Z', (7.56,2.52), layer=34, texttype=10))
gf180mcu_fd_sc_mcu7t5v0_.add(gdstk.Label('A1', (2.52,1.96), layer=34, texttype=10))
gf180mcu_fd_sc_mcu7t5v0_.add(gdstk.Label('A2', (2.52,2.52), layer=34, texttype=10))
gf180mcu_fd_sc_mcu7t5v0_.add(gdstk.Label('& Vendor GLOBALFOUNDRIES', (0,2), layer=63, texttype=63))
gf180mcu_fd_sc_mcu7t5v0_.add(gdstk.Label('& Product GF018hv5v_mcu_sc7', (0,1.5), layer=63, texttype=63))
gf180mcu_fd_sc_mcu7t5v0_.add(gdstk.Label('& Version 2015q2v1', (0,1), layer=63, texttype=63))
gf180mcu_fd_sc_mcu7t5v0_.add(gdstk.Label('& Metric 1.00', (0,0.5), layer=63, texttype=63))
gf180mcu_fd_sc_mcu7t5v0_.add(gdstk.Label('VNW', (0.345,3.92), layer=21, texttype=10))
gf180mcu_fd_sc_mcu7t5v0_.add(gdstk.Label('VPW', (0.34,-0.085), layer=204, texttype=10))

lib.write_gds('gf180mcu_fd_sc_mcu7t5v0__or2_4.gds')
